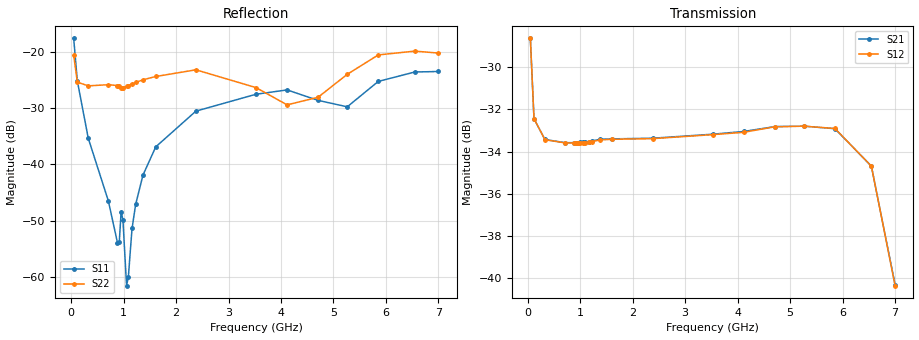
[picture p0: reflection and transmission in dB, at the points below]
! Integrated Device Technology
! Corporate Headquarters
! 6024 Silver Creek Valley Road
! San Jose, CA 95138  USA
! Phone:  1-408-284-8200
! Toll Free:  1-800-223-1366
! Webpage:  http://www.idt.com/
! Timing and RF Division
! 515 Groton Road, Suite 102
! Westford, MA 01886-6024
! Device:  F2258
! Description: Voltage Variable RF Attenuator
! Frequency:  50.0 -  6000.00 MHz
! Package:  3x3 mm Thin QFN Plastic Package: 16 pin
! Ports:  2 RF, 2 DC
!  Pin  1  = NC
!  Pin  2  = NC
!  Pin  3  = RF2  = Port 2
!  Pin  4  = GND
!  Pin  5  = Vdd
!  Pin  6  = NC
!  Pin  7  = VCTRL
!  Pin  8  = NC
!  Pin  9  = GND
!  Pin 10  = RF1  = Port 1
!  Pin 11  = NC
!  Pin 12  = NC
!  Pin 13  = NC
!  Pin 14  = NC
!  Pin 15  = NC
!  Pin 16  = NC
! Vcntrl:  1.810 Volts
! Vdd:  +3.300 Volts
! Current:  1.156 mA
! Data:  The device was measured on a the F2258 evaluation board which has
!  individual transmission lines to the RF pins.  Data was collected
!  using a calibrated network analyzer.  The evaluation board was
!  de-embedded using a TRL calibration technique.
!  The reference plane is the edge of the package pin.
! Misc:  SN 10
!  Action Tracker AT0285
! Date Measured:  2014-12-10
! Date:  2016-01-13  MJV
! Note:
!  Integrated Device Technology supplies this data as a sample of measured
!  data at the package pin for this product.  Your particular data for this
!  product may vary.
!  Data was taken at 25 degrees C.
!  Integrated Device Technology reserves the right to change this data at anytime.
!Freq_(GHz)  S11M_(dB)  S11P_(deg)  S21M_(dB)  S21P_(deg)  S12M_(dB)  S12P_(deg)  S22M_(dB)  S22P_(deg)
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# GHz S dB R 50
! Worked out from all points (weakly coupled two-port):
!   201 points, 50 MHz to 7 GHz, reference 50 ohm
!   highest |S21| = -28.65 dB at 50 MHz (marker M1); lowest = -40.3 dB at 7 GHz (marker M2)
!   lowest |S11| = -61.6 dB at 1.058 GHz (marker M3), VSWR 1.00, Z = 49.9 + j0.0425 ohm
!   |S11| at or under -10 dB: start of sweep to end of sweep
!   |S22| runs from -29.8 to -19.5 dB; largest |S21 - S12| = 0.00011
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0.05  -17.54 -110.6  -28.65 -61.0  -28.65 -61.0  -20.51 -92.3
0.1195  -25.12 -106.3  -32.45 -32.2  -32.44 -32.2  -25.33 -45.3
0.328  -35.33 -113.4  -33.43 -14.1  -33.44 -14.1  -26.00 -15.2
0.71025  -46.47 -132.2  -33.58 -9.7  -33.59 -9.7  -25.79 -5.7
0.884  -53.91 167.2  -33.58 -9.4  -33.60 -9.4  -25.94 -6.2
0.91875  -53.88 147.2  -33.58 -9.4  -33.60 -9.4  -25.96 -6.3
0.9535  -48.43 -158.5  -33.59 -9.4  -33.61 -9.4  -26.45 -4.0
0.98825  -49.83 -171.0  -33.57 -9.4  -33.60 -9.4  -26.36 -4.8
1.05775  -61.58 149.3  -33.56 -9.4  -33.60 -9.4  -26.08 -4.6
1.0925  -59.95 102.5  -33.55 -9.5  -33.58 -9.4  -25.97 -4.7
1.162  -51.39 60.3  -33.53 -9.6  -33.55 -9.6  -25.66 -4.8
1.2315  -47.09 41.1  -33.50 -9.8  -33.53 -9.8  -25.39 -5.0
1.3705  -41.88 34.1  -33.42 -10.5  -33.45 -10.5  -24.92 -5.0
1.61375  -36.86 31.1  -33.40 -12.0  -33.42 -12.0  -24.33 -6.0
2.37825  -30.50 47.3  -33.37 -16.6  -33.39 -16.6  -23.14 -6.2
3.525  -27.49 91.2  -33.18 -24.4  -33.20 -24.3  -26.31 -1.5
4.11575  -26.72 104.8  -33.05 -28.9  -33.09 -28.8  -29.38 -6.3
4.7065  -28.58 95.3  -32.82 -34.3  -32.83 -34.2  -28.03 -21.8
5.2625  -29.73 53.6  -32.80 -40.4  -32.80 -40.4  -23.94 -32.1
5.85325  -25.21 29.4  -32.92 -50.3  -32.91 -50.3  -20.49 -35.4
6.54825  -23.53 44.8  -34.69 -68.3  -34.69 -68.3  -19.81 -62.3
7  -23.44 84.3  -40.29 -65.6  -40.34 -65.4  -20.16 -123.5
